VERSION 5.7 ;
BUSBITCHARS "[]" ;
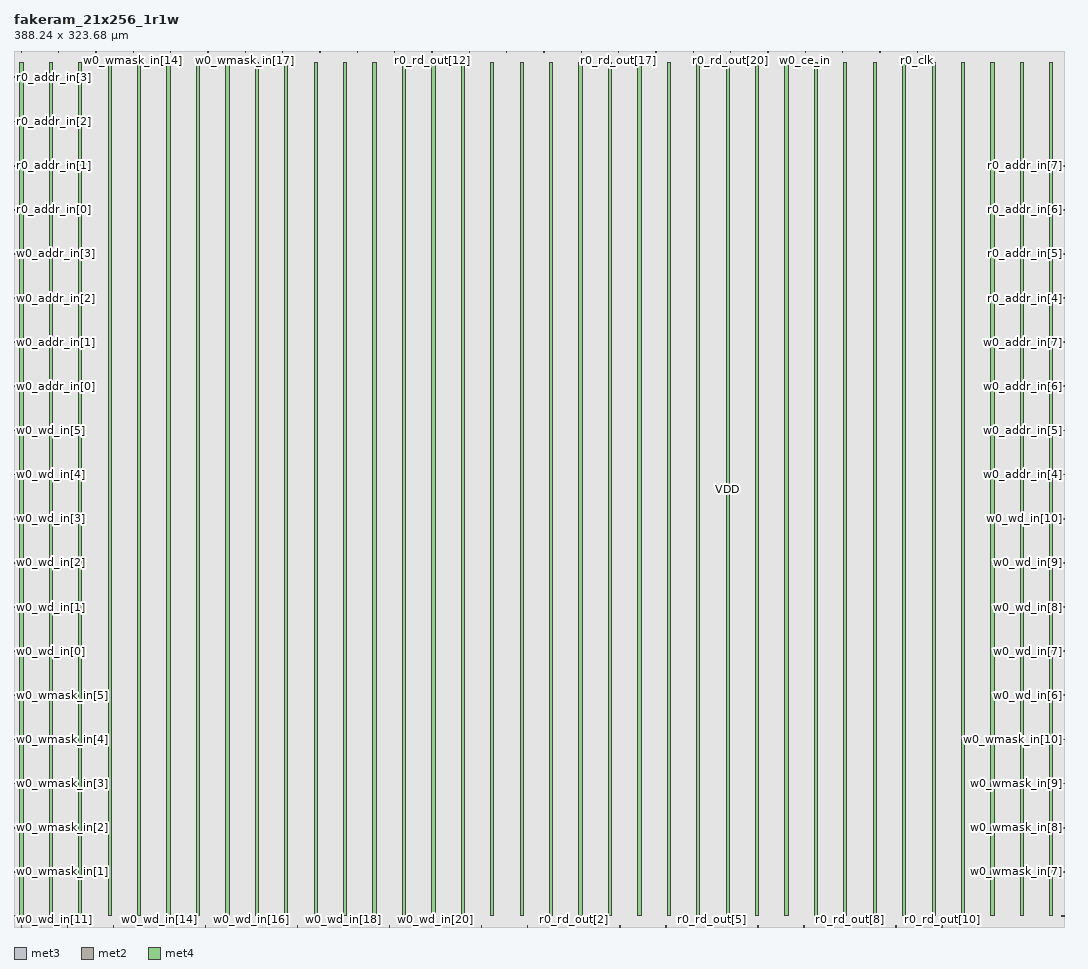
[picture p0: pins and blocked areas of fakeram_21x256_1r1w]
MACRO fakeram_21x256_1r1w
  FOREIGN fakeram_21x256_1r1w 0 0 ;
  SYMMETRY X Y R90 ;
  SIZE 388.240 BY 323.680 ;
  CLASS BLOCK ;
  PIN w0_wmask_in[0]
    DIRECTION INPUT ;
    USE SIGNAL ;
    SHAPE ABUTMENT ;
    PORT
      LAYER met3 ;
      RECT 0.000 3.930 0.900 4.230 ;
    END
  END w0_wmask_in[0]
  PIN w0_wmask_in[1]
    DIRECTION INPUT ;
    USE SIGNAL ;
    SHAPE ABUTMENT ;
    PORT
      LAYER met3 ;
      RECT 0.000 20.250 0.900 20.550 ;
    END
  END w0_wmask_in[1]
  PIN w0_wmask_in[2]
    DIRECTION INPUT ;
    USE SIGNAL ;
    SHAPE ABUTMENT ;
    PORT
      LAYER met3 ;
      RECT 0.000 36.570 0.900 36.870 ;
    END
  END w0_wmask_in[2]
  PIN w0_wmask_in[3]
    DIRECTION INPUT ;
    USE SIGNAL ;
    SHAPE ABUTMENT ;
    PORT
      LAYER met3 ;
      RECT 0.000 52.890 0.900 53.190 ;
    END
  END w0_wmask_in[3]
  PIN w0_wmask_in[4]
    DIRECTION INPUT ;
    USE SIGNAL ;
    SHAPE ABUTMENT ;
    PORT
      LAYER met3 ;
      RECT 0.000 69.210 0.900 69.510 ;
    END
  END w0_wmask_in[4]
  PIN w0_wmask_in[5]
    DIRECTION INPUT ;
    USE SIGNAL ;
    SHAPE ABUTMENT ;
    PORT
      LAYER met3 ;
      RECT 0.000 85.530 0.900 85.830 ;
    END
  END w0_wmask_in[5]
  PIN w0_wmask_in[6]
    DIRECTION INPUT ;
    USE SIGNAL ;
    SHAPE ABUTMENT ;
    PORT
      LAYER met3 ;
      RECT 387.340 3.930 388.240 4.230 ;
    END
  END w0_wmask_in[6]
  PIN w0_wmask_in[7]
    DIRECTION INPUT ;
    USE SIGNAL ;
    SHAPE ABUTMENT ;
    PORT
      LAYER met3 ;
      RECT 387.340 20.250 388.240 20.550 ;
    END
  END w0_wmask_in[7]
  PIN w0_wmask_in[8]
    DIRECTION INPUT ;
    USE SIGNAL ;
    SHAPE ABUTMENT ;
    PORT
      LAYER met3 ;
      RECT 387.340 36.570 388.240 36.870 ;
    END
  END w0_wmask_in[8]
  PIN w0_wmask_in[9]
    DIRECTION INPUT ;
    USE SIGNAL ;
    SHAPE ABUTMENT ;
    PORT
      LAYER met3 ;
      RECT 387.340 52.890 388.240 53.190 ;
    END
  END w0_wmask_in[9]
  PIN w0_wmask_in[10]
    DIRECTION INPUT ;
    USE SIGNAL ;
    SHAPE ABUTMENT ;
    PORT
      LAYER met3 ;
      RECT 387.340 69.210 388.240 69.510 ;
    END
  END w0_wmask_in[10]
  PIN w0_wmask_in[11]
    DIRECTION INPUT ;
    USE SIGNAL ;
    SHAPE ABUTMENT ;
    PORT
      LAYER met2 ;
      RECT 2.690 323.260 2.830 323.680 ;
    END
  END w0_wmask_in[11]
  PIN w0_wmask_in[12]
    DIRECTION INPUT ;
    USE SIGNAL ;
    SHAPE ABUTMENT ;
    PORT
      LAYER met2 ;
      RECT 16.490 323.260 16.630 323.680 ;
    END
  END w0_wmask_in[12]
  PIN w0_wmask_in[13]
    DIRECTION INPUT ;
    USE SIGNAL ;
    SHAPE ABUTMENT ;
    PORT
      LAYER met2 ;
      RECT 30.290 323.260 30.430 323.680 ;
    END
  END w0_wmask_in[13]
  PIN w0_wmask_in[14]
    DIRECTION INPUT ;
    USE SIGNAL ;
    SHAPE ABUTMENT ;
    PORT
      LAYER met2 ;
      RECT 44.090 323.260 44.230 323.680 ;
    END
  END w0_wmask_in[14]
  PIN w0_wmask_in[15]
    DIRECTION INPUT ;
    USE SIGNAL ;
    SHAPE ABUTMENT ;
    PORT
      LAYER met2 ;
      RECT 57.890 323.260 58.030 323.680 ;
    END
  END w0_wmask_in[15]
  PIN w0_wmask_in[16]
    DIRECTION INPUT ;
    USE SIGNAL ;
    SHAPE ABUTMENT ;
    PORT
      LAYER met2 ;
      RECT 71.690 323.260 71.830 323.680 ;
    END
  END w0_wmask_in[16]
  PIN w0_wmask_in[17]
    DIRECTION INPUT ;
    USE SIGNAL ;
    SHAPE ABUTMENT ;
    PORT
      LAYER met2 ;
      RECT 85.490 323.260 85.630 323.680 ;
    END
  END w0_wmask_in[17]
  PIN w0_wmask_in[18]
    DIRECTION INPUT ;
    USE SIGNAL ;
    SHAPE ABUTMENT ;
    PORT
      LAYER met2 ;
      RECT 99.290 323.260 99.430 323.680 ;
    END
  END w0_wmask_in[18]
  PIN w0_wmask_in[19]
    DIRECTION INPUT ;
    USE SIGNAL ;
    SHAPE ABUTMENT ;
    PORT
      LAYER met2 ;
      RECT 113.090 323.260 113.230 323.680 ;
    END
  END w0_wmask_in[19]
  PIN w0_wmask_in[20]
    DIRECTION INPUT ;
    USE SIGNAL ;
    SHAPE ABUTMENT ;
    PORT
      LAYER met2 ;
      RECT 126.890 323.260 127.030 323.680 ;
    END
  END w0_wmask_in[20]
  PIN w0_wd_in[0]
    DIRECTION INPUT ;
    USE SIGNAL ;
    SHAPE ABUTMENT ;
    PORT
      LAYER met3 ;
      RECT 0.000 101.850 0.900 102.150 ;
    END
  END w0_wd_in[0]
  PIN w0_wd_in[1]
    DIRECTION INPUT ;
    USE SIGNAL ;
    SHAPE ABUTMENT ;
    PORT
      LAYER met3 ;
      RECT 0.000 118.170 0.900 118.470 ;
    END
  END w0_wd_in[1]
  PIN w0_wd_in[2]
    DIRECTION INPUT ;
    USE SIGNAL ;
    SHAPE ABUTMENT ;
    PORT
      LAYER met3 ;
      RECT 0.000 134.490 0.900 134.790 ;
    END
  END w0_wd_in[2]
  PIN w0_wd_in[3]
    DIRECTION INPUT ;
    USE SIGNAL ;
    SHAPE ABUTMENT ;
    PORT
      LAYER met3 ;
      RECT 0.000 150.810 0.900 151.110 ;
    END
  END w0_wd_in[3]
  PIN w0_wd_in[4]
    DIRECTION INPUT ;
    USE SIGNAL ;
    SHAPE ABUTMENT ;
    PORT
      LAYER met3 ;
      RECT 0.000 167.130 0.900 167.430 ;
    END
  END w0_wd_in[4]
  PIN w0_wd_in[5]
    DIRECTION INPUT ;
    USE SIGNAL ;
    SHAPE ABUTMENT ;
    PORT
      LAYER met3 ;
      RECT 0.000 183.450 0.900 183.750 ;
    END
  END w0_wd_in[5]
  PIN w0_wd_in[6]
    DIRECTION INPUT ;
    USE SIGNAL ;
    SHAPE ABUTMENT ;
    PORT
      LAYER met3 ;
      RECT 387.340 85.530 388.240 85.830 ;
    END
  END w0_wd_in[6]
  PIN w0_wd_in[7]
    DIRECTION INPUT ;
    USE SIGNAL ;
    SHAPE ABUTMENT ;
    PORT
      LAYER met3 ;
      RECT 387.340 101.850 388.240 102.150 ;
    END
  END w0_wd_in[7]
  PIN w0_wd_in[8]
    DIRECTION INPUT ;
    USE SIGNAL ;
    SHAPE ABUTMENT ;
    PORT
      LAYER met3 ;
      RECT 387.340 118.170 388.240 118.470 ;
    END
  END w0_wd_in[8]
  PIN w0_wd_in[9]
    DIRECTION INPUT ;
    USE SIGNAL ;
    SHAPE ABUTMENT ;
    PORT
      LAYER met3 ;
      RECT 387.340 134.490 388.240 134.790 ;
    END
  END w0_wd_in[9]
  PIN w0_wd_in[10]
    DIRECTION INPUT ;
    USE SIGNAL ;
    SHAPE ABUTMENT ;
    PORT
      LAYER met3 ;
      RECT 387.340 150.810 388.240 151.110 ;
    END
  END w0_wd_in[10]
  PIN w0_wd_in[11]
    DIRECTION OUTPUT ;
    USE SIGNAL ;
    SHAPE ABUTMENT ;
    PORT
      LAYER met2 ;
      RECT 2.690 0.000 2.830 0.420 ;
    END
  END w0_wd_in[11]
  PIN w0_wd_in[12]
    DIRECTION OUTPUT ;
    USE SIGNAL ;
    SHAPE ABUTMENT ;
    PORT
      LAYER met2 ;
      RECT 19.710 0.000 19.850 0.420 ;
    END
  END w0_wd_in[12]
  PIN w0_wd_in[13]
    DIRECTION OUTPUT ;
    USE SIGNAL ;
    SHAPE ABUTMENT ;
    PORT
      LAYER met2 ;
      RECT 36.730 0.000 36.870 0.420 ;
    END
  END w0_wd_in[13]
  PIN w0_wd_in[14]
    DIRECTION OUTPUT ;
    USE SIGNAL ;
    SHAPE ABUTMENT ;
    PORT
      LAYER met2 ;
      RECT 53.750 0.000 53.890 0.420 ;
    END
  END w0_wd_in[14]
  PIN w0_wd_in[15]
    DIRECTION OUTPUT ;
    USE SIGNAL ;
    SHAPE ABUTMENT ;
    PORT
      LAYER met2 ;
      RECT 70.770 0.000 70.910 0.420 ;
    END
  END w0_wd_in[15]
  PIN w0_wd_in[16]
    DIRECTION OUTPUT ;
    USE SIGNAL ;
    SHAPE ABUTMENT ;
    PORT
      LAYER met2 ;
      RECT 87.790 0.000 87.930 0.420 ;
    END
  END w0_wd_in[16]
  PIN w0_wd_in[17]
    DIRECTION OUTPUT ;
    USE SIGNAL ;
    SHAPE ABUTMENT ;
    PORT
      LAYER met2 ;
      RECT 104.810 0.000 104.950 0.420 ;
    END
  END w0_wd_in[17]
  PIN w0_wd_in[18]
    DIRECTION OUTPUT ;
    USE SIGNAL ;
    SHAPE ABUTMENT ;
    PORT
      LAYER met2 ;
      RECT 121.830 0.000 121.970 0.420 ;
    END
  END w0_wd_in[18]
  PIN w0_wd_in[19]
    DIRECTION OUTPUT ;
    USE SIGNAL ;
    SHAPE ABUTMENT ;
    PORT
      LAYER met2 ;
      RECT 138.850 0.000 138.990 0.420 ;
    END
  END w0_wd_in[19]
  PIN w0_wd_in[20]
    DIRECTION OUTPUT ;
    USE SIGNAL ;
    SHAPE ABUTMENT ;
    PORT
      LAYER met2 ;
      RECT 155.870 0.000 156.010 0.420 ;
    END
  END w0_wd_in[20]
  PIN r0_rd_out[0]
    DIRECTION OUTPUT ;
    USE SIGNAL ;
    SHAPE ABUTMENT ;
    PORT
      LAYER met2 ;
      RECT 172.890 0.000 173.030 0.420 ;
    END
  END r0_rd_out[0]
  PIN r0_rd_out[1]
    DIRECTION OUTPUT ;
    USE SIGNAL ;
    SHAPE ABUTMENT ;
    PORT
      LAYER met2 ;
      RECT 189.910 0.000 190.050 0.420 ;
    END
  END r0_rd_out[1]
  PIN r0_rd_out[2]
    DIRECTION OUTPUT ;
    USE SIGNAL ;
    SHAPE ABUTMENT ;
    PORT
      LAYER met2 ;
      RECT 206.930 0.000 207.070 0.420 ;
    END
  END r0_rd_out[2]
  PIN r0_rd_out[3]
    DIRECTION OUTPUT ;
    USE SIGNAL ;
    SHAPE ABUTMENT ;
    PORT
      LAYER met2 ;
      RECT 223.950 0.000 224.090 0.420 ;
    END
  END r0_rd_out[3]
  PIN r0_rd_out[4]
    DIRECTION OUTPUT ;
    USE SIGNAL ;
    SHAPE ABUTMENT ;
    PORT
      LAYER met2 ;
      RECT 240.970 0.000 241.110 0.420 ;
    END
  END r0_rd_out[4]
  PIN r0_rd_out[5]
    DIRECTION OUTPUT ;
    USE SIGNAL ;
    SHAPE ABUTMENT ;
    PORT
      LAYER met2 ;
      RECT 257.990 0.000 258.130 0.420 ;
    END
  END r0_rd_out[5]
  PIN r0_rd_out[6]
    DIRECTION OUTPUT ;
    USE SIGNAL ;
    SHAPE ABUTMENT ;
    PORT
      LAYER met2 ;
      RECT 275.010 0.000 275.150 0.420 ;
    END
  END r0_rd_out[6]
  PIN r0_rd_out[7]
    DIRECTION OUTPUT ;
    USE SIGNAL ;
    SHAPE ABUTMENT ;
    PORT
      LAYER met2 ;
      RECT 292.030 0.000 292.170 0.420 ;
    END
  END r0_rd_out[7]
  PIN r0_rd_out[8]
    DIRECTION OUTPUT ;
    USE SIGNAL ;
    SHAPE ABUTMENT ;
    PORT
      LAYER met2 ;
      RECT 309.050 0.000 309.190 0.420 ;
    END
  END r0_rd_out[8]
  PIN r0_rd_out[9]
    DIRECTION OUTPUT ;
    USE SIGNAL ;
    SHAPE ABUTMENT ;
    PORT
      LAYER met2 ;
      RECT 326.070 0.000 326.210 0.420 ;
    END
  END r0_rd_out[9]
  PIN r0_rd_out[10]
    DIRECTION OUTPUT ;
    USE SIGNAL ;
    SHAPE ABUTMENT ;
    PORT
      LAYER met2 ;
      RECT 343.090 0.000 343.230 0.420 ;
    END
  END r0_rd_out[10]
  PIN r0_rd_out[11]
    DIRECTION OUTPUT ;
    USE SIGNAL ;
    SHAPE ABUTMENT ;
    PORT
      LAYER met2 ;
      RECT 140.690 323.260 140.830 323.680 ;
    END
  END r0_rd_out[11]
  PIN r0_rd_out[12]
    DIRECTION OUTPUT ;
    USE SIGNAL ;
    SHAPE ABUTMENT ;
    PORT
      LAYER met2 ;
      RECT 154.490 323.260 154.630 323.680 ;
    END
  END r0_rd_out[12]
  PIN r0_rd_out[13]
    DIRECTION OUTPUT ;
    USE SIGNAL ;
    SHAPE ABUTMENT ;
    PORT
      LAYER met2 ;
      RECT 168.290 323.260 168.430 323.680 ;
    END
  END r0_rd_out[13]
  PIN r0_rd_out[14]
    DIRECTION OUTPUT ;
    USE SIGNAL ;
    SHAPE ABUTMENT ;
    PORT
      LAYER met2 ;
      RECT 182.090 323.260 182.230 323.680 ;
    END
  END r0_rd_out[14]
  PIN r0_rd_out[15]
    DIRECTION OUTPUT ;
    USE SIGNAL ;
    SHAPE ABUTMENT ;
    PORT
      LAYER met2 ;
      RECT 195.890 323.260 196.030 323.680 ;
    END
  END r0_rd_out[15]
  PIN r0_rd_out[16]
    DIRECTION OUTPUT ;
    USE SIGNAL ;
    SHAPE ABUTMENT ;
    PORT
      LAYER met2 ;
      RECT 209.690 323.260 209.830 323.680 ;
    END
  END r0_rd_out[16]
  PIN r0_rd_out[17]
    DIRECTION OUTPUT ;
    USE SIGNAL ;
    SHAPE ABUTMENT ;
    PORT
      LAYER met2 ;
      RECT 223.490 323.260 223.630 323.680 ;
    END
  END r0_rd_out[17]
  PIN r0_rd_out[18]
    DIRECTION OUTPUT ;
    USE SIGNAL ;
    SHAPE ABUTMENT ;
    PORT
      LAYER met2 ;
      RECT 237.290 323.260 237.430 323.680 ;
    END
  END r0_rd_out[18]
  PIN r0_rd_out[19]
    DIRECTION OUTPUT ;
    USE SIGNAL ;
    SHAPE ABUTMENT ;
    PORT
      LAYER met2 ;
      RECT 251.090 323.260 251.230 323.680 ;
    END
  END r0_rd_out[19]
  PIN r0_rd_out[20]
    DIRECTION OUTPUT ;
    USE SIGNAL ;
    SHAPE ABUTMENT ;
    PORT
      LAYER met2 ;
      RECT 264.890 323.260 265.030 323.680 ;
    END
  END r0_rd_out[20]
  PIN w0_addr_in[0]
    DIRECTION INPUT ;
    USE SIGNAL ;
    SHAPE ABUTMENT ;
    PORT
      LAYER met3 ;
      RECT 0.000 199.770 0.900 200.070 ;
    END
  END w0_addr_in[0]
  PIN w0_addr_in[1]
    DIRECTION INPUT ;
    USE SIGNAL ;
    SHAPE ABUTMENT ;
    PORT
      LAYER met3 ;
      RECT 0.000 216.090 0.900 216.390 ;
    END
  END w0_addr_in[1]
  PIN w0_addr_in[2]
    DIRECTION INPUT ;
    USE SIGNAL ;
    SHAPE ABUTMENT ;
    PORT
      LAYER met3 ;
      RECT 0.000 232.410 0.900 232.710 ;
    END
  END w0_addr_in[2]
  PIN w0_addr_in[3]
    DIRECTION INPUT ;
    USE SIGNAL ;
    SHAPE ABUTMENT ;
    PORT
      LAYER met3 ;
      RECT 0.000 248.730 0.900 249.030 ;
    END
  END w0_addr_in[3]
  PIN w0_addr_in[4]
    DIRECTION INPUT ;
    USE SIGNAL ;
    SHAPE ABUTMENT ;
    PORT
      LAYER met3 ;
      RECT 387.340 167.130 388.240 167.430 ;
    END
  END w0_addr_in[4]
  PIN w0_addr_in[5]
    DIRECTION INPUT ;
    USE SIGNAL ;
    SHAPE ABUTMENT ;
    PORT
      LAYER met3 ;
      RECT 387.340 183.450 388.240 183.750 ;
    END
  END w0_addr_in[5]
  PIN w0_addr_in[6]
    DIRECTION INPUT ;
    USE SIGNAL ;
    SHAPE ABUTMENT ;
    PORT
      LAYER met3 ;
      RECT 387.340 199.770 388.240 200.070 ;
    END
  END w0_addr_in[6]
  PIN w0_addr_in[7]
    DIRECTION INPUT ;
    USE SIGNAL ;
    SHAPE ABUTMENT ;
    PORT
      LAYER met3 ;
      RECT 387.340 216.090 388.240 216.390 ;
    END
  END w0_addr_in[7]
  PIN r0_addr_in[0]
    DIRECTION INPUT ;
    USE SIGNAL ;
    SHAPE ABUTMENT ;
    PORT
      LAYER met3 ;
      RECT 0.000 265.050 0.900 265.350 ;
    END
  END r0_addr_in[0]
  PIN r0_addr_in[1]
    DIRECTION INPUT ;
    USE SIGNAL ;
    SHAPE ABUTMENT ;
    PORT
      LAYER met3 ;
      RECT 0.000 281.370 0.900 281.670 ;
    END
  END r0_addr_in[1]
  PIN r0_addr_in[2]
    DIRECTION INPUT ;
    USE SIGNAL ;
    SHAPE ABUTMENT ;
    PORT
      LAYER met3 ;
      RECT 0.000 297.690 0.900 297.990 ;
    END
  END r0_addr_in[2]
  PIN r0_addr_in[3]
    DIRECTION INPUT ;
    USE SIGNAL ;
    SHAPE ABUTMENT ;
    PORT
      LAYER met3 ;
      RECT 0.000 314.010 0.900 314.310 ;
    END
  END r0_addr_in[3]
  PIN r0_addr_in[4]
    DIRECTION INPUT ;
    USE SIGNAL ;
    SHAPE ABUTMENT ;
    PORT
      LAYER met3 ;
      RECT 387.340 232.410 388.240 232.710 ;
    END
  END r0_addr_in[4]
  PIN r0_addr_in[5]
    DIRECTION INPUT ;
    USE SIGNAL ;
    SHAPE ABUTMENT ;
    PORT
      LAYER met3 ;
      RECT 387.340 248.730 388.240 249.030 ;
    END
  END r0_addr_in[5]
  PIN r0_addr_in[6]
    DIRECTION INPUT ;
    USE SIGNAL ;
    SHAPE ABUTMENT ;
    PORT
      LAYER met3 ;
      RECT 387.340 265.050 388.240 265.350 ;
    END
  END r0_addr_in[6]
  PIN r0_addr_in[7]
    DIRECTION INPUT ;
    USE SIGNAL ;
    SHAPE ABUTMENT ;
    PORT
      LAYER met3 ;
      RECT 387.340 281.370 388.240 281.670 ;
    END
  END r0_addr_in[7]
  PIN w0_we_in
    DIRECTION INPUT ;
    USE SIGNAL ;
    SHAPE ABUTMENT ;
    PORT
      LAYER met2 ;
      RECT 278.690 323.260 278.830 323.680 ;
    END
  END w0_we_in
  PIN w0_ce_in
    DIRECTION INPUT ;
    USE SIGNAL ;
    SHAPE ABUTMENT ;
    PORT
      LAYER met2 ;
      RECT 292.490 323.260 292.630 323.680 ;
    END
  END w0_ce_in
  PIN w0_clk
    DIRECTION INPUT ;
    USE SIGNAL ;
    SHAPE ABUTMENT ;
    PORT
      LAYER met2 ;
      RECT 306.290 323.260 306.430 323.680 ;
    END
  END w0_clk
  PIN r0_ce_in
    DIRECTION INPUT ;
    USE SIGNAL ;
    SHAPE ABUTMENT ;
    PORT
      LAYER met2 ;
      RECT 320.090 323.260 320.230 323.680 ;
    END
  END r0_ce_in
  PIN r0_clk
    DIRECTION INPUT ;
    USE SIGNAL ;
    SHAPE ABUTMENT ;
    PORT
      LAYER met2 ;
      RECT 333.890 323.260 334.030 323.680 ;
    END
  END r0_clk
  PIN VSS
    DIRECTION INOUT ;
    USE GROUND ;
    PORT
      LAYER met4 ;
      RECT 2.160 4.080 3.360 319.600 ;
      RECT 13.040 4.080 14.240 319.600 ;
      RECT 23.920 4.080 25.120 319.600 ;
      RECT 34.800 4.080 36.000 319.600 ;
      RECT 45.680 4.080 46.880 319.600 ;
      RECT 56.560 4.080 57.760 319.600 ;
      RECT 67.440 4.080 68.640 319.600 ;
      RECT 78.320 4.080 79.520 319.600 ;
      RECT 89.200 4.080 90.400 319.600 ;
      RECT 100.080 4.080 101.280 319.600 ;
      RECT 110.960 4.080 112.160 319.600 ;
      RECT 121.840 4.080 123.040 319.600 ;
      RECT 132.720 4.080 133.920 319.600 ;
      RECT 143.600 4.080 144.800 319.600 ;
      RECT 154.480 4.080 155.680 319.600 ;
      RECT 165.360 4.080 166.560 319.600 ;
      RECT 176.240 4.080 177.440 319.600 ;
      RECT 187.120 4.080 188.320 319.600 ;
      RECT 198.000 4.080 199.200 319.600 ;
      RECT 208.880 4.080 210.080 319.600 ;
      RECT 219.760 4.080 220.960 319.600 ;
      RECT 230.640 4.080 231.840 319.600 ;
      RECT 241.520 4.080 242.720 319.600 ;
      RECT 252.400 4.080 253.600 319.600 ;
      RECT 263.280 4.080 264.480 319.600 ;
      RECT 274.160 4.080 275.360 319.600 ;
      RECT 285.040 4.080 286.240 319.600 ;
      RECT 295.920 4.080 297.120 319.600 ;
      RECT 306.800 4.080 308.000 319.600 ;
      RECT 317.680 4.080 318.880 319.600 ;
      RECT 328.560 4.080 329.760 319.600 ;
      RECT 339.440 4.080 340.640 319.600 ;
      RECT 350.320 4.080 351.520 319.600 ;
      RECT 361.200 4.080 362.400 319.600 ;
      RECT 372.080 4.080 373.280 319.600 ;
      RECT 382.960 4.080 384.160 319.600 ;
    END
  END VSS
  PIN VDD
    DIRECTION INOUT ;
    USE POWER ;
    PORT
      LAYER met4 ;
      RECT 2.160 4.080 3.360 319.600 ;
      RECT 13.040 4.080 14.240 319.600 ;
      RECT 23.920 4.080 25.120 319.600 ;
      RECT 34.800 4.080 36.000 319.600 ;
      RECT 45.680 4.080 46.880 319.600 ;
      RECT 56.560 4.080 57.760 319.600 ;
      RECT 67.440 4.080 68.640 319.600 ;
      RECT 78.320 4.080 79.520 319.600 ;
      RECT 89.200 4.080 90.400 319.600 ;
      RECT 100.080 4.080 101.280 319.600 ;
      RECT 110.960 4.080 112.160 319.600 ;
      RECT 121.840 4.080 123.040 319.600 ;
      RECT 132.720 4.080 133.920 319.600 ;
      RECT 143.600 4.080 144.800 319.600 ;
      RECT 154.480 4.080 155.680 319.600 ;
      RECT 165.360 4.080 166.560 319.600 ;
      RECT 176.240 4.080 177.440 319.600 ;
      RECT 187.120 4.080 188.320 319.600 ;
      RECT 198.000 4.080 199.200 319.600 ;
      RECT 208.880 4.080 210.080 319.600 ;
      RECT 219.760 4.080 220.960 319.600 ;
      RECT 230.640 4.080 231.840 319.600 ;
      RECT 241.520 4.080 242.720 319.600 ;
      RECT 252.400 4.080 253.600 319.600 ;
      RECT 263.280 4.080 264.480 319.600 ;
      RECT 274.160 4.080 275.360 319.600 ;
      RECT 285.040 4.080 286.240 319.600 ;
      RECT 295.920 4.080 297.120 319.600 ;
      RECT 306.800 4.080 308.000 319.600 ;
      RECT 317.680 4.080 318.880 319.600 ;
      RECT 328.560 4.080 329.760 319.600 ;
      RECT 339.440 4.080 340.640 319.600 ;
      RECT 350.320 4.080 351.520 319.600 ;
      RECT 361.200 4.080 362.400 319.600 ;
      RECT 372.080 4.080 373.280 319.600 ;
      RECT 382.960 4.080 384.160 319.600 ;
    END
  END VDD
  OBS
    LAYER met1 ;
    RECT 0 0 388.240 323.680 ;
    LAYER met2 ;
    RECT 0 0 388.240 323.680 ;
    LAYER met3 ;
    RECT 0 0 388.240 323.680 ;
    LAYER met4 ;
    RECT 0 0 388.240 323.680 ;
  END
END fakeram_21x256_1r1w

END LIBRARY
